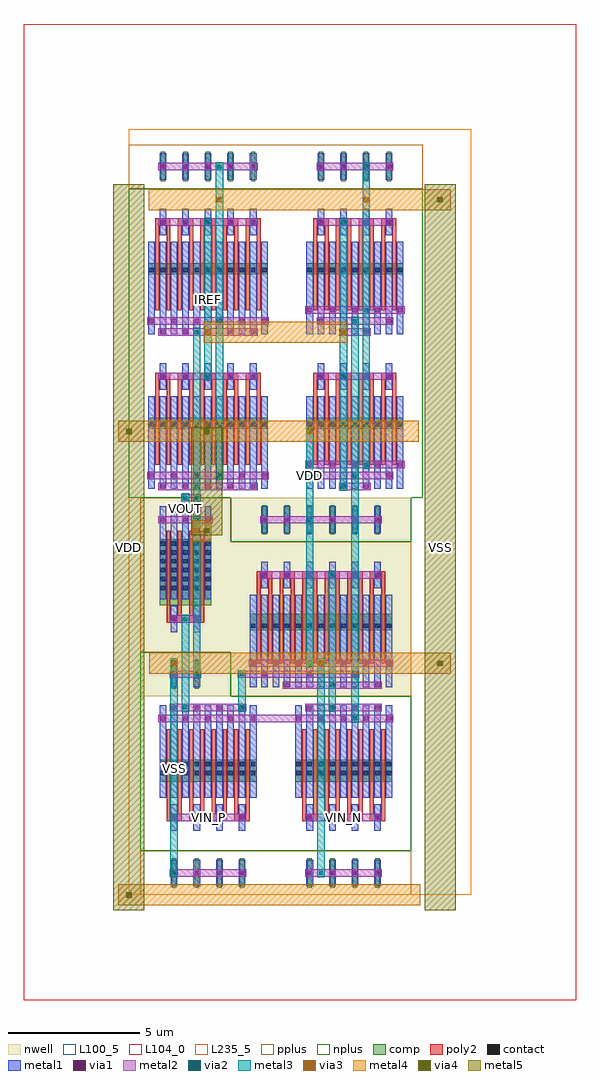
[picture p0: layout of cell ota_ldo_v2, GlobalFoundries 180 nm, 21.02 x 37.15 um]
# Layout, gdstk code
from math import pi, radians
import gdstk
lib = gdstk.Library(unit=1e-6, precision=1e-09)
def R(c, l, rs):  # rectangles x0, y0, x1, y1
    for r in rs: c.add(gdstk.rectangle(r[:2], r[2:], *l))
def A(c, l, x, y, w, h, nx, ny, dx, dy):  # array of equal rectangles
    R(c, l, [(x+i*dx, y+j*dy, x+i*dx+w, y+j*dy+h) for i in range(nx) for j in range(ny)])
def P(c, l, *ps):  # polygons
    for p in ps: c.add(gdstk.Polygon(p, *l))
nwell = (21, 0)
comp = (22, 0)
poly2 = (30, 0)
pplus = (31, 0)
nplus = (32, 0)
contact = (33, 0)
metal1 = (34, 0)
via1 = (35, 0)
metal2 = (36, 0)
via2 = (38, 0)
via3 = (40, 0)
via4 = (41, 0)
metal3 = (42, 0)
metal4 = (46, 0)
metal5 = (81, 0)
L100_5 = (100, 5)
L104_0 = (104, 0)
L235_5 = (235, 5)

current_mirror_nmos = lib.new_cell('CURRENT_MIRROR_NMOS')
A(current_mirror_nmos, comp, 1.205, 12.04, 0.17, 1.12, 4, 1, 0.86, 0)
R(current_mirror_nmos, comp, [(0.735,2.625,4.425,3.045), (0.735,8.505,4.425,8.925)])
A(current_mirror_nmos, poly2, 1, 1.26, 0.15, 3.36, 8, 2, 0.43, 5.88)
A(current_mirror_nmos, poly2, 1, 4.485, 0.58, 0.27, 4, 2, 0.86, 5.88)
R(current_mirror_nmos, pplus, [(0,11.76,5.16,13.44)])
R(current_mirror_nmos, nplus, [(0,0,5.16,11.76)])
A(current_mirror_nmos, contact, 0.775, 2.705, 0.17, 0.17, 3, 2, 0.43, 5.88)
A(current_mirror_nmos, contact, 1.635, 2.705, 0.17, 0.17, 3, 2, 0.43, 5.88)
A(current_mirror_nmos, contact, 2.495, 2.705, 0.17, 0.17, 3, 2, 0.43, 5.88)
A(current_mirror_nmos, contact, 3.355, 2.705, 0.17, 0.17, 3, 2, 0.43, 5.88)
A(current_mirror_nmos, contact, 1.205, 4.535, 0.17, 0.17, 4, 2, 0.86, 5.88)
R(current_mirror_nmos, contact, [(1.205,12.515,1.375,12.685), (1.205,12.515,1.375,12.685), (2.065,12.515,2.235,12.685), (2.065,12.515,2.235,12.685), (2.925,12.515,3.095,12.685), (2.925,12.515,3.095,12.685), (3.785,12.515,3.955,12.685), (3.785,12.515,3.955,12.685)])
A(current_mirror_nmos, metal1, 0.735, 0.335, 0.25, 3.53, 9, 2, 0.43, 5.88)
A(current_mirror_nmos, metal1, 1.165, 4.115, 0.25, 1.01, 4, 2, 0.86, 5.88)
A(current_mirror_nmos, metal1, 1.165, 12.095, 0.25, 1.01, 4, 1, 0.86, 0)
A(current_mirror_nmos, via1, 0.775, 1.175, 0.17, 0.17, 5, 2, 0.86, 5.88)
A(current_mirror_nmos, via1, 1.205, 4.535, 0.17, 0.17, 4, 2, 0.86, 5.88)
A(current_mirror_nmos, via1, 1.205, 12.515, 0.17, 0.17, 4, 1, 0.86, 0)
R(current_mirror_nmos, via1, [(2.065,0.335,2.235,0.505), (2.925,0.335,3.095,0.505), (1.205,0.755,1.375,0.925), (3.785,0.755,3.955,0.925), (2.065,6.215,2.235,6.385), (2.925,6.215,3.095,6.385), (1.205,6.635,1.375,6.805), (3.785,6.635,3.955,6.805)])
R(current_mirror_nmos, metal2, [(1.98,0.28,3.18,0.56), (1.12,0.7,4.04,0.98), (0.69,1.12,4.47,1.4), (1.12,4.48,4.04,4.76), (1.98,6.16,3.18,6.44), (1.12,6.58,4.04,6.86), (0.69,7,4.47,7.28), (1.12,10.36,4.04,10.64), (1.12,12.46,4.04,12.74)])
R(current_mirror_nmos, via2, [(2.075,0.345,2.225,0.495), (2.505,0.765,2.655,0.915), (2.935,1.185,3.085,1.335), (2.075,4.545,2.225,4.695), (2.075,6.225,2.225,6.375), (2.505,6.645,2.655,6.795), (2.935,7.065,3.085,7.215), (2.075,10.425,2.225,10.575), (2.935,12.525,3.085,12.675)])
R(current_mirror_nmos, metal3, [(2.01,0.26,2.29,10.66), (2.44,0.68,2.72,6.88), (2.87,1.1,3.15,12.76)])
R(current_mirror_nmos, L100_5, [(0,0,5.16,13.44)])

out_nmos = lib.new_cell('OUT_NMOS')
A(out_nmos, comp, 1.205, 12.04, 0.17, 1.12, 5, 1, 0.86, 0)
R(out_nmos, comp, [(0.735,2.625,5.285,3.045), (0.735,8.505,5.285,8.925)])
A(out_nmos, poly2, 1, 1.26, 0.15, 3.36, 10, 2, 0.43, 5.88)
A(out_nmos, poly2, 1, 4.485, 0.58, 0.27, 5, 2, 0.86, 5.88)
R(out_nmos, pplus, [(0,11.76,6.02,13.44)])
R(out_nmos, nplus, [(0,0,6.02,11.76)])
A(out_nmos, contact, 0.775, 2.705, 0.17, 0.17, 3, 2, 0.43, 5.88)
A(out_nmos, contact, 1.635, 2.705, 0.17, 0.17, 3, 2, 0.43, 5.88)
A(out_nmos, contact, 2.495, 2.705, 0.17, 0.17, 3, 2, 0.43, 5.88)
A(out_nmos, contact, 3.355, 2.705, 0.17, 0.17, 3, 2, 0.43, 5.88)
A(out_nmos, contact, 4.215, 2.705, 0.17, 0.17, 3, 2, 0.43, 5.88)
A(out_nmos, contact, 1.205, 4.535, 0.17, 0.17, 5, 2, 0.86, 5.88)
R(out_nmos, contact, [(1.205,12.515,1.375,12.685), (1.205,12.515,1.375,12.685), (2.065,12.515,2.235,12.685), (2.065,12.515,2.235,12.685), (2.925,12.515,3.095,12.685), (2.925,12.515,3.095,12.685), (3.785,12.515,3.955,12.685), (3.785,12.515,3.955,12.685), (4.645,12.515,4.815,12.685), (4.645,12.515,4.815,12.685)])
A(out_nmos, metal1, 0.735, 0.335, 0.25, 3.53, 11, 2, 0.43, 5.88)
A(out_nmos, metal1, 1.165, 4.115, 0.25, 1.01, 5, 2, 0.86, 5.88)
A(out_nmos, metal1, 1.165, 12.095, 0.25, 1.01, 5, 1, 0.86, 0)
A(out_nmos, via1, 1.205, 0.335, 0.17, 0.17, 5, 2, 0.86, 4.2)
A(out_nmos, via1, 0.775, 0.755, 0.17, 0.17, 6, 2, 0.86, 5.88)
A(out_nmos, via1, 1.205, 6.215, 0.17, 0.17, 5, 2, 0.86, 4.2)
A(out_nmos, via1, 1.205, 12.515, 0.17, 0.17, 5, 1, 0.86, 0)
R(out_nmos, metal2, [(1.12,0.28,4.9,0.56), (0.69,0.7,5.33,0.98), (1.12,4.48,4.9,4.76), (1.12,6.16,4.9,6.44), (0.69,6.58,5.33,6.86), (1.12,10.36,4.9,10.64), (1.12,12.46,4.9,12.74)])
A(out_nmos, via2, 3.365, 0.765, 0.15, 0.15, 1, 3, 0, 5.88)
R(out_nmos, via2, [(2.505,0.345,2.655,0.495), (2.935,4.545,3.085,4.695), (2.505,6.225,2.655,6.375), (2.935,10.425,3.085,10.575)])
R(out_nmos, metal3, [(2.44,0.26,2.72,6.46), (3.3,0.68,3.58,12.76), (2.87,4.46,3.15,10.66)])
R(out_nmos, L100_5, [(0,0,6.02,13.44)])

cmb_nmos_2_39468839_pg0_ = lib.new_cell('CMB_NMOS_2_39468839_PG0_0_0_1710993508')
R(cmb_nmos_2_39468839_pg0_, via3, [(2.91,6.2,3.11,6.4), (2.91,6.2,3.11,6.4), (8.07,6.2,8.27,6.4), (8.07,6.2,8.27,6.4)])
R(cmb_nmos_2_39468839_pg0_, metal3, [(2.87,6.115,3.15,6.485), (2.87,6.115,3.15,6.485), (8.03,6.115,8.31,6.485), (8.03,6.115,8.31,6.485)])
P(cmb_nmos_2_39468839_pg0_, metal3, [(0,0),(0,0),(0,0),(0,0)],
  [(0,0),(0,0),(0,0),(0,0)],
  [(0,0),(0,0),(0,0),(0,0)],
  [(0,0),(0,0),(0,0),(0,0)],
  [(0,0),(0,0),(0,0),(0,0)],
  [(0,0),(0,0),(0,0),(0,0)])
R(cmb_nmos_2_39468839_pg0_, metal4, [(2.845,5.9,3.175,6.7), (2.845,5.9,3.175,6.7), (3.01,5.9,8.17,6.7), (8.005,5.9,8.335,6.7), (8.005,5.9,8.335,6.7)])
R(cmb_nmos_2_39468839_pg0_, L235_5, [(0,0,11.18,13.44)])
cmb_nmos_2_39468839_pg0_.add(gdstk.Reference(current_mirror_nmos, (6.02,0)))
cmb_nmos_2_39468839_pg0_.add(gdstk.Reference(out_nmos, (0,0)))

current_mirror_pmos = lib.new_cell('CURRENT_MIRROR_PMOS')
R(current_mirror_pmos, nwell, [(0,0,6.88,7.56)])
A(current_mirror_pmos, comp, 1.205, 6.16, 0.17, 1.12, 6, 1, 0.86, 0)
R(current_mirror_pmos, comp, [(0.735,2.52,6.145,3.15)])
A(current_mirror_pmos, poly2, 1, 1.26, 0.15, 3.36, 12, 1, 0.43, 0)
A(current_mirror_pmos, poly2, 1, 4.485, 0.58, 0.27, 6, 1, 0.86, 0)
R(current_mirror_pmos, pplus, [(0,0,6.88,5.88)])
R(current_mirror_pmos, nplus, [(0,5.88,6.88,7.56)])
A(current_mirror_pmos, contact, 0.775, 2.6, 0.17, 0.17, 3, 1, 0.43, 0)
A(current_mirror_pmos, contact, 1.635, 2.6, 0.17, 0.17, 3, 1, 0.43, 0)
A(current_mirror_pmos, contact, 2.495, 2.6, 0.17, 0.17, 3, 1, 0.43, 0)
A(current_mirror_pmos, contact, 3.355, 2.6, 0.17, 0.17, 3, 1, 0.43, 0)
A(current_mirror_pmos, contact, 4.215, 2.6, 0.17, 0.17, 3, 1, 0.43, 0)
A(current_mirror_pmos, contact, 5.075, 2.6, 0.17, 0.17, 3, 1, 0.43, 0)
A(current_mirror_pmos, contact, 1.205, 4.535, 0.17, 0.17, 6, 2, 0.86, 2.1)
A(current_mirror_pmos, metal1, 0.735, 0.335, 0.25, 3.53, 13, 1, 0.43, 0)
A(current_mirror_pmos, metal1, 1.165, 4.115, 0.25, 1.01, 6, 2, 0.86, 2.1)
A(current_mirror_pmos, via1, 1.205, 0.335, 0.17, 0.17, 3, 1, 1.72, 0)
A(current_mirror_pmos, via1, 2.065, 0.755, 0.17, 0.17, 3, 1, 1.72, 0)
A(current_mirror_pmos, via1, 0.775, 1.175, 0.17, 0.17, 7, 1, 0.86, 0)
A(current_mirror_pmos, via1, 1.205, 4.535, 0.17, 0.17, 6, 2, 0.86, 2.1)
R(current_mirror_pmos, metal2, [(1.12,0.28,4.9,0.56), (1.98,0.7,5.76,0.98), (0.69,1.12,6.19,1.4), (1.12,4.48,5.76,4.76), (1.12,6.58,5.76,6.86)])
R(current_mirror_pmos, via2, [(2.935,0.345,3.085,0.495), (3.795,1.185,3.945,1.335), (2.935,4.545,3.085,4.695), (3.795,6.645,3.945,6.795)])
R(current_mirror_pmos, metal3, [(2.87,0.26,3.15,4.78), (3.73,1.1,4.01,6.88)])
R(current_mirror_pmos, L100_5, [(0,0,6.88,7.56)])

out_pmos = lib.new_cell('OUT_PMOS')
R(out_pmos, nwell, [(0,0,3.44,7.56)])
R(out_pmos, comp, [(0.735,1.575,2.705,4.095), (1.205,6.16,1.375,7.28), (2.065,6.16,2.235,7.28)])
A(out_pmos, poly2, 1, 1.26, 0.15, 3.36, 4, 1, 0.43, 0)
R(out_pmos, poly2, [(1,4.485,1.58,4.755), (1.86,4.485,2.44,4.755)])
R(out_pmos, pplus, [(0,0,3.44,5.88)])
R(out_pmos, nplus, [(0,5.88,3.44,7.56)])
A(out_pmos, contact, 0.775, 1.655, 0.17, 0.17, 3, 6, 0.43, 0.34)
A(out_pmos, contact, 1.635, 1.655, 0.17, 0.17, 3, 6, 0.43, 0.34)
R(out_pmos, contact, [(1.205,4.535,1.375,4.705), (2.065,4.535,2.235,4.705), (1.205,6.635,1.375,6.805), (2.065,6.635,2.235,6.805)])
A(out_pmos, metal1, 0.735, 0.335, 0.25, 3.53, 5, 1, 0.43, 0)
R(out_pmos, metal1, [(1.165,4.115,1.415,5.125), (2.025,4.115,2.275,5.125), (1.165,6.215,1.415,7.225), (2.025,6.215,2.275,7.225)])
A(out_pmos, via1, 0.775, 0.755, 0.17, 0.17, 3, 1, 0.86, 0)
R(out_pmos, via1, [(1.205,0.335,1.375,0.505), (2.065,0.335,2.235,0.505), (1.205,4.535,1.375,4.705), (2.065,4.535,2.235,4.705), (1.205,6.635,1.375,6.805), (2.065,6.635,2.235,6.805)])
R(out_pmos, metal2, [(1.12,0.28,2.32,0.56), (0.69,0.7,2.75,0.98), (1.12,4.48,2.32,4.76), (1.12,6.58,2.32,6.86)])
R(out_pmos, via2, [(2.075,0.765,2.225,0.915), (2.075,6.645,2.225,6.795)])
R(out_pmos, metal3, [(2.01,0.68,2.29,6.88)])
R(out_pmos, L100_5, [(0,0,3.44,7.56)])

nmos_diff_pair_original = lib.new_cell('NMOS_DIFF_PAIR_ORIGINAL')
A(nmos_diff_pair_original, comp, 1.205, 6.16, 0.17, 1.12, 4, 1, 0.86, 0)
R(nmos_diff_pair_original, comp, [(0.735,2.415,4.425,3.255)])
A(nmos_diff_pair_original, poly2, 1, 1.26, 0.15, 3.36, 8, 1, 0.43, 0)
A(nmos_diff_pair_original, poly2, 1, 4.485, 0.58, 0.27, 4, 1, 0.86, 0)
R(nmos_diff_pair_original, pplus, [(0,5.88,5.16,7.56)])
R(nmos_diff_pair_original, nplus, [(0,0,5.16,5.88)])
A(nmos_diff_pair_original, contact, 0.775, 2.495, 0.17, 0.17, 3, 2, 0.43, 0.34)
A(nmos_diff_pair_original, contact, 1.635, 2.495, 0.17, 0.17, 3, 2, 0.43, 0.34)
A(nmos_diff_pair_original, contact, 2.495, 2.495, 0.17, 0.17, 3, 2, 0.43, 0.34)
A(nmos_diff_pair_original, contact, 3.355, 2.495, 0.17, 0.17, 3, 2, 0.43, 0.34)
A(nmos_diff_pair_original, contact, 1.205, 4.535, 0.17, 0.17, 4, 2, 0.86, 2.1)
A(nmos_diff_pair_original, metal1, 0.735, 0.335, 0.25, 3.53, 9, 1, 0.43, 0)
A(nmos_diff_pair_original, metal1, 1.165, 4.115, 0.25, 1.01, 4, 2, 0.86, 2.1)
A(nmos_diff_pair_original, via1, 1.205, 0.335, 0.17, 0.17, 4, 2, 0.86, 4.2)
A(nmos_diff_pair_original, via1, 0.775, 0.755, 0.17, 0.17, 5, 1, 0.86, 0)
A(nmos_diff_pair_original, via1, 1.205, 6.635, 0.17, 0.17, 4, 1, 0.86, 0)
R(nmos_diff_pair_original, metal2, [(1.12,0.28,4.04,0.56), (0.69,0.7,4.47,0.98), (1.12,4.48,4.04,4.76), (1.12,6.58,4.04,6.86)])
R(nmos_diff_pair_original, L100_5, [(0,0,5.16,7.56)])

ota_ldo_v2 = lib.new_cell('ota_ldo_v2')
R(ota_ldo_v2, metal2, [(1.56,0.7,1.88,0.98), (1.56,0.7,1.88,0.98), (1.56,0.7,1.88,0.98), (1.56,0.7,1.88,0.98), (1.56,0.7,1.88,0.98), (7.15,0.7,7.47,0.98), (7.15,0.7,7.47,0.98), (7.15,0.7,7.47,0.98), (7.15,0.7,7.47,0.98), (4.73,6.58,6.45,6.86), (8.44,6.58,8.76,6.86), (8.44,6.58,8.76,6.86), (1.99,7,2.31,7.28), (1.99,7,2.31,7.28), (1.99,7,2.31,7.28), (1.99,7,2.31,7.28), (4.14,7,4.46,7.28), (4.14,7,4.46,7.28), (7.58,7,7.9,7.28), (7.58,7,7.9,7.28), (4.14,8.26,4.46,8.54), (4.14,8.26,4.46,8.54), (4.3,8.26,5.16,8.54), (1.99,10.36,2.31,10.64), (1.99,10.36,2.31,10.64), (1.99,10.36,2.31,10.64), (1.99,10.36,2.31,10.64), (1.99,14.56,2.31,14.84), (1.99,14.56,2.31,14.84), (1.99,14.98,2.31,15.26), (1.99,14.98,2.31,15.26), (2.15,14.98,2.58,15.26), (2.42,14.98,2.74,15.26), (2.42,14.98,2.74,15.26)])
P(ota_ldo_v2, metal2, [(0,0),(0,0),(0,0),(0,0)],
  [(0,0),(0,0),(0,0),(0,0)],
  [(0,0),(0,0),(0,0),(0,0)],
  [(0,0),(0,0),(0,0),(0,0)],
  [(0,0),(0,0),(0,0),(0,0)],
  [(0,0),(0,0),(0,0),(0,0)],
  [(0,0),(0,0),(0,0),(0,0)],
  [(0,0),(0,0),(0,0),(0,0)],
  [(0,0),(0,0),(0,0),(0,0)],
  [(0,0),(0,0),(0,0),(0,0)],
  [(0,0),(0,0),(0,0),(0,0)],
  [(0,0),(0,0),(0,0),(0,0)],
  [(0,0),(0,0),(0,0),(0,0)],
  [(0,0),(0,0),(0,0),(0,0)])
R(ota_ldo_v2, via2, [(1.645,0.765,1.795,0.915), (1.645,0.765,1.795,0.915), (1.645,0.765,1.795,0.915), (1.645,0.765,1.795,0.915), (1.645,0.765,1.795,0.915), (7.235,0.765,7.385,0.915), (7.235,0.765,7.385,0.915), (7.235,0.765,7.385,0.915), (7.235,0.765,7.385,0.915), (8.525,6.645,8.675,6.795), (8.525,6.645,8.675,6.795), (2.075,7.065,2.225,7.215), (2.075,7.065,2.225,7.215), (2.075,7.065,2.225,7.215), (2.075,7.065,2.225,7.215), (4.225,7.065,4.375,7.215), (4.225,7.065,4.375,7.215), (7.665,7.065,7.815,7.215), (7.665,7.065,7.815,7.215), (4.225,8.325,4.375,8.475), (4.225,8.325,4.375,8.475), (2.075,10.425,2.225,10.575), (2.075,10.425,2.225,10.575), (2.075,10.425,2.225,10.575), (2.075,10.425,2.225,10.575), (2.075,14.625,2.225,14.775), (2.075,14.625,2.225,14.775), (2.075,15.045,2.225,15.195), (2.075,15.045,2.225,15.195), (2.505,15.045,2.655,15.195), (2.505,15.045,2.655,15.195)])
R(ota_ldo_v2, via3, [(1.62,8.72,1.82,8.92), (1.62,8.72,1.82,8.92), (1.62,8.72,1.82,8.92), (1.62,8.72,1.82,8.92), (1.62,8.72,1.82,8.92), (7.21,8.72,7.41,8.92), (7.21,8.72,7.41,8.92), (7.21,8.72,7.41,8.92), (7.21,8.72,7.41,8.92), (2.48,13.76,2.68,13.96), (2.48,13.76,2.68,13.96), (6.78,17.54,6.98,17.74), (6.78,17.54,6.98,17.74), (6.78,17.54,6.98,17.74), (3.34,26.36,3.54,26.56), (3.34,26.36,3.54,26.56), (8.93,26.36,9.13,26.56), (8.93,26.36,9.13,26.56), (8.93,26.36,9.13,26.56)])
R(ota_ldo_v2, via4, [(-0.1,-0.1,0.1,0.1), (11.74,8.72,11.94,8.92), (2.86,13.76,3.06,13.96), (2.86,13.76,3.06,13.96), (-0.1,17.54,0.1,17.74), (2.86,17.54,3.06,17.74), (2.86,17.54,3.06,17.74), (11.74,26.36,11.94,26.56)])
R(ota_ldo_v2, metal3, [(1.58,0.68,1.86,1), (1.58,0.68,1.86,1), (1.58,0.68,1.86,1), (1.58,0.68,1.86,1), (1.58,0.68,1.86,1), (7.17,0.68,7.45,1), (7.17,0.68,7.45,1), (7.17,0.68,7.45,1), (7.17,0.68,7.45,1), (1.58,0.84,1.86,8.82), (7.17,0.84,7.45,8.82), (8.46,6.56,8.74,6.88), (8.46,6.56,8.74,6.88), (8.46,6.72,8.74,15.96), (2.01,6.98,2.29,7.3), (2.01,6.98,2.29,7.3), (2.01,6.98,2.29,7.3), (2.01,6.98,2.29,7.3), (4.16,6.98,4.44,7.3), (4.16,6.98,4.44,7.3), (7.6,6.98,7.88,7.3), (7.6,6.98,7.88,7.3), (2.01,7.14,2.29,10.5), (4.16,7.14,4.44,8.4), (7.6,7.14,7.88,7.98), (4.16,8.24,4.44,8.56), (4.16,8.24,4.44,8.56), (1.58,8.635,1.86,9.005), (1.58,8.635,1.86,9.005), (1.58,8.635,1.86,9.005), (1.58,8.635,1.86,9.005), (1.58,8.635,1.86,9.005), (7.17,8.635,7.45,9.005), (7.17,8.635,7.45,9.005), (7.17,8.635,7.45,9.005), (7.17,8.635,7.45,9.005), (2.01,10.34,2.29,10.66), (2.01,10.34,2.29,10.66), (2.01,10.34,2.29,10.66), (2.01,10.34,2.29,10.66), (2.44,13.675,2.72,14.045), (2.44,13.675,2.72,14.045), (6.74,14.28,7.02,17.64), (2.01,14.54,2.29,14.86), (2.01,14.54,2.29,14.86), (2.01,14.7,2.29,15.12), (2.01,14.96,2.29,15.28), (2.01,14.96,2.29,15.28), (2.44,14.96,2.72,15.28), (2.44,14.96,2.72,15.28), (2.44,15.12,2.72,15.54), (6.74,17.455,7.02,17.825), (6.74,17.455,7.02,17.825), (6.74,17.455,7.02,17.825), (3.3,26.275,3.58,26.645), (3.3,26.275,3.58,26.645), (8.89,26.275,9.17,26.645), (8.89,26.275,9.17,26.645), (8.89,26.275,9.17,26.645)])
P(ota_ldo_v2, metal3, [(0,0),(0,0),(0,0),(0,0)],
  [(0,0),(0,0),(0,0),(0,0)],
  [(0,0),(0,0),(0,0),(0,0)],
  [(0,0),(0,0),(0,0),(0,0)],
  [(0,0),(0,0),(0,0),(0,0)],
  [(0,0),(0,0),(0,0),(0,0)],
  [(0,0),(0,0),(0,0),(0,0)],
  [(0,0),(0,0),(0,0),(0,0)],
  [(0,0),(0,0),(0,0),(0,0)],
  [(0,0),(0,0),(0,0),(0,0)])
A(ota_ldo_v2, metal4, -0.4, -0.4, 4.24, 0.8, 3, 2, 3.44, 17.64)
R(ota_ldo_v2, metal4, [(-0.165,-0.4,0.165,0.4), (9.92,-0.4,11.09,0.4), (0.77,8.42,3.84,9.22), (1.555,8.42,1.885,9.22), (1.555,8.42,1.885,9.22), (1.555,8.42,1.885,9.22), (1.555,8.42,1.885,9.22), (1.555,8.42,1.885,9.22), (3.04,8.42,7.28,9.22), (6.48,8.42,10.72,9.22), (7.145,8.42,7.475,9.22), (7.145,8.42,7.475,9.22), (7.145,8.42,7.475,9.22), (7.145,8.42,7.475,9.22), (9.92,8.42,12.24,9.22), (11.675,8.42,12.005,9.22), (2.415,13.46,2.745,14.26), (2.415,13.46,2.745,14.26), (2.58,13.46,2.96,14.26), (2.795,13.46,3.125,14.26), (2.795,13.46,3.125,14.26), (-0.165,17.24,0.165,18.04), (2.795,17.24,3.125,18.04), (2.795,17.24,3.125,18.04), (6.715,17.24,7.045,18.04), (6.715,17.24,7.045,18.04), (6.715,17.24,7.045,18.04), (9.92,17.24,11.03,18.04), (0.75,26.06,3.84,26.86), (3.04,26.06,7.28,26.86), (3.275,26.06,3.605,26.86), (3.275,26.06,3.605,26.86), (6.48,26.06,10.72,26.86), (8.865,26.06,9.195,26.86), (8.865,26.06,9.195,26.86), (8.865,26.06,9.195,26.86), (9.92,26.06,12.24,26.86), (11.675,26.06,12.005,26.86)])
P(ota_ldo_v2, metal4, [(0,0),(0,0),(0,0),(0,0)])
A(ota_ldo_v2, metal5, -0.59, -0.59, 1.18, 10, 1, 3, 0, 8.82)
A(ota_ldo_v2, metal5, 11.25, -0.59, 1.18, 10, 1, 3, 0, 8.82)
R(ota_ldo_v2, metal5, [(-0.59,-0.165,0.59,0.165), (11.25,8.655,12.43,8.985), (2.37,13.695,3.55,14.025), (2.37,13.695,3.55,14.025), (2.37,13.86,3.55,17.64), (-0.59,17.475,0.59,17.805), (2.37,17.475,3.55,17.805), (2.37,17.475,3.55,17.805), (11.25,26.295,12.43,26.625)])
R(ota_ldo_v2, L104_0, [(-4,-4,17.02,33.15)])
R(ota_ldo_v2, L235_5, [(0,0,13.02,29.15)])
ota_ldo_v2.add(gdstk.Reference(cmb_nmos_2_39468839_pg0_, (0,15.12)))
ota_ldo_v2.add(gdstk.Reference(current_mirror_pmos, (10.75,7.56), rotation=pi, x_reflection=True))
ota_ldo_v2.add(gdstk.Reference(out_pmos, (0.43,15.12), x_reflection=True))
ota_ldo_v2.add(gdstk.Reference(nmos_diff_pair_original, (5.59,7.56), rotation=pi))
ota_ldo_v2.add(gdstk.Reference(nmos_diff_pair_original, (5.59,7.56), x_reflection=True))
ota_ldo_v2.add(gdstk.Label('VSS', (11.84,13.23), layer=81, texttype=10))
ota_ldo_v2.add(gdstk.Label('VSS', (11.84,13.23), layer=81, texttype=10))
ota_ldo_v2.add(gdstk.Label('VSS', (11.84,13.23), layer=81, texttype=10))
ota_ldo_v2.add(gdstk.Label('VSS', (11.84,13.23), layer=81, texttype=10))
ota_ldo_v2.add(gdstk.Label('VSS', (11.84,13.23), layer=81, texttype=10))
ota_ldo_v2.add(gdstk.Label('VSS', (11.84,13.23), layer=81, texttype=10))
ota_ldo_v2.add(gdstk.Label('VSS', (11.84,13.23), layer=81, texttype=10))
ota_ldo_v2.add(gdstk.Label('VSS', (11.84,13.23), layer=81, texttype=10))
ota_ldo_v2.add(gdstk.Label('VSS', (11.84,13.23), layer=81, texttype=10))
ota_ldo_v2.add(gdstk.Label('VSS', (11.84,13.23), layer=81, texttype=10))
ota_ldo_v2.add(gdstk.Label('VDD', (0,13.23), layer=81, texttype=10))
ota_ldo_v2.add(gdstk.Label('VDD', (0,13.23), layer=81, texttype=10))
ota_ldo_v2.add(gdstk.Label('VDD', (0,13.23), layer=81, texttype=10))
ota_ldo_v2.add(gdstk.Label('VDD', (0,13.23), layer=81, texttype=10))
ota_ldo_v2.add(gdstk.Label('VDD', (0,13.23), layer=81, texttype=10))
ota_ldo_v2.add(gdstk.Label('VDD', (0,13.23), layer=81, texttype=10))
ota_ldo_v2.add(gdstk.Label('VOUT', (2.15,14.7), layer=36, texttype=10))
ota_ldo_v2.add(gdstk.Label('VIN_P', (3.01,2.94), layer=36, texttype=10))
ota_ldo_v2.add(gdstk.Label('VIN_N', (8.17,2.94), layer=36, texttype=10))
ota_ldo_v2.add(gdstk.Label('IREF', (3.01,22.68), layer=42, texttype=10))
ota_ldo_v2.add(gdstk.Label('VSS', (1.72,4.83), layer=42, texttype=10))
ota_ldo_v2.add(gdstk.Label('VDD', (6.88,15.96), layer=42, texttype=10))

lib.write_gds('ota_ldo_v2.gds')
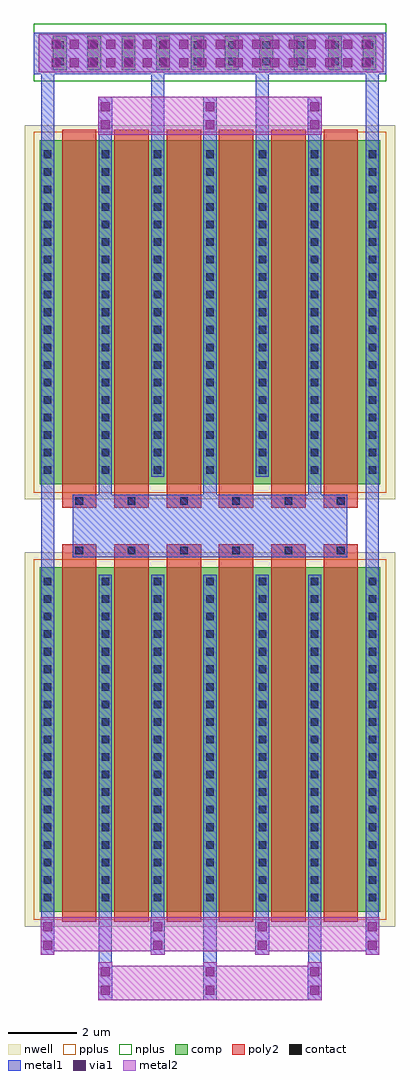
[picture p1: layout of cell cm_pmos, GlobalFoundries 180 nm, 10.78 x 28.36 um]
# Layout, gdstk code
from math import pi, radians
import gdstk
lib = gdstk.Library(unit=1e-6, precision=1e-09)
def R(c, l, rs):  # rectangles x0, y0, x1, y1
    for r in rs: c.add(gdstk.rectangle(r[:2], r[2:], *l))
def A(c, l, x, y, w, h, nx, ny, dx, dy):  # array of equal rectangles
    R(c, l, [(x+i*dx, y+j*dy, x+i*dx+w, y+j*dy+h) for i in range(nx) for j in range(ny)])
nwell = (21, 0)
comp = (22, 0)
poly2 = (30, 0)
pplus = (31, 0)
nplus = (32, 0)
contact = (33, 0)
metal1 = (34, 0)
via1 = (35, 0)
metal2 = (36, 0)

pfet_2 = lib.new_cell('pfet$2')
R(pfet_2, nwell, [(-0.9,-0.44,9.88,10.44)])
R(pfet_2, comp, [(-0.46,0,0,10), (0,0,8.98,10), (8.98,0,9.44,10)])
A(pfet_2, poly2, 0.19, -0.3, 1, 10.6, 6, 1, 1.52, 0)
A(pfet_2, poly2, 0.19, 10.3, 1, 0.38, 6, 1, 1.52, 0)
R(pfet_2, pplus, [(-0.63,-0.24,9.61,10.24)])
A(pfet_2, contact, -0.34, 0.3, 0.22, 0.22, 1, 19, 0, 0.51)
A(pfet_2, contact, 1.34, 0.3, 0.22, 0.22, 5, 19, 1.52, 0.51)
A(pfet_2, contact, 9.1, 0.3, 0.22, 0.22, 1, 19, 0, 0.51)
A(pfet_2, contact, 0.58, 10.38, 0.22, 0.22, 6, 1, 1.52, 0)
A(pfet_2, metal1, 1.26, 0.22, 0.38, 9.56, 5, 1, 1.52, 0)
A(pfet_2, metal1, 0.5, 10.299, 0.38, 0.382, 6, 1, 1.52, 0)
R(pfet_2, metal1, [(-0.42,0.22,-0.04,9.78), (9.02,0.22,9.4,9.78)])

via_dev_4 = lib.new_cell('via_dev$4')
R(via_dev_4, comp, [(0,0,0.4,1)])
R(via_dev_4, contact, [(0.09,0.15,0.31,0.37), (0.09,0.63,0.31,0.85)])
R(via_dev_4, metal1, [(0,0,0.4,1)])

via_dev_11 = lib.new_cell('via_dev$11')
R(via_dev_11, metal1, [(0,0,10,1.1)])
A(via_dev_11, via1, 0.365, 0.155, 0.26, 0.26, 18, 2, 0.53, 0.53)
R(via_dev_11, metal2, [(0,0,10,1.1)])

via_dev_3 = lib.new_cell('via_dev$3')
R(via_dev_3, metal1, [(0,0,0.4,1.1)])
R(via_dev_3, via1, [(0.07,0.155,0.33,0.415), (0.07,0.685,0.33,0.945)])
R(via_dev_3, metal2, [(0,0,0.4,1.1)])

cm_pmos = lib.new_cell('cm_pmos')
R(cm_pmos, nplus, [(0.27,26.695,10.51,28.36)])
A(cm_pmos, metal1, 2.16, 1.1, 0.38, 1.69, 3, 1, 3.04, 0)
A(cm_pmos, metal1, 2.16, 14.686, 0.38, 0.519, 3, 1, 3.04, 0)
A(cm_pmos, metal1, 2.16, 24.765, 0.38, 0.38, 3, 1, 3.04, 0)
R(cm_pmos, metal1, [(0.48,2.41,0.86,2.79), (0.48,2.41,0.86,2.79), (3.68,2.41,4.06,2.79), (6.72,2.41,7.1,2.79), (9.92,2.41,10.3,2.79), (9.92,2.41,10.3,2.79), (0.48,12.35,0.86,15.205), (9.92,12.35,10.3,15.205), (1.4,12.869,9.38,14.686), (0.48,24.765,0.86,26.905), (3.68,24.765,4.06,26.905), (6.72,24.765,7.1,26.905), (8.24,24.765,8.62,25.145), (9.92,24.765,10.3,26.905), (0.27,26.905,10.51,28.105), (0.27,26.905,10.51,28.105)])
R(cm_pmos, metal2, [(2.15,0,8.63,1), (0.47,1.41,10.31,2.41), (2.15,25.145,8.63,26.245)])
cm_pmos.add(gdstk.Reference(pfet_2, (0.9,2.57)))
cm_pmos.add(gdstk.Reference(pfet_2, (9.88,24.985), rotation=pi))
r = gdstk.Reference(via_dev_4, (0.825,27.015)); r.repetition = gdstk.Repetition(10, 1, v1=(1,0), v2=(0,0)); cm_pmos.add(r)
cm_pmos.add(gdstk.Reference(via_dev_11, (0.42,26.955)))
cm_pmos.add(gdstk.Reference(via_dev_3, (9.91,1.31)))
cm_pmos.add(gdstk.Reference(via_dev_3, (2.15,0)))
cm_pmos.add(gdstk.Reference(via_dev_3, (5.19,0)))
cm_pmos.add(gdstk.Reference(via_dev_3, (8.23,0)))
cm_pmos.add(gdstk.Reference(via_dev_3, (0.47,1.31)))
cm_pmos.add(gdstk.Reference(via_dev_3, (3.67,1.31)))
cm_pmos.add(gdstk.Reference(via_dev_3, (6.71,1.31)))
cm_pmos.add(gdstk.Reference(via_dev_3, (5.19,25.145)))
cm_pmos.add(gdstk.Reference(via_dev_3, (2.15,25.145)))
cm_pmos.add(gdstk.Reference(via_dev_3, (8.23,25.145)))

lib.write_gds('cm_pmos.gds')
